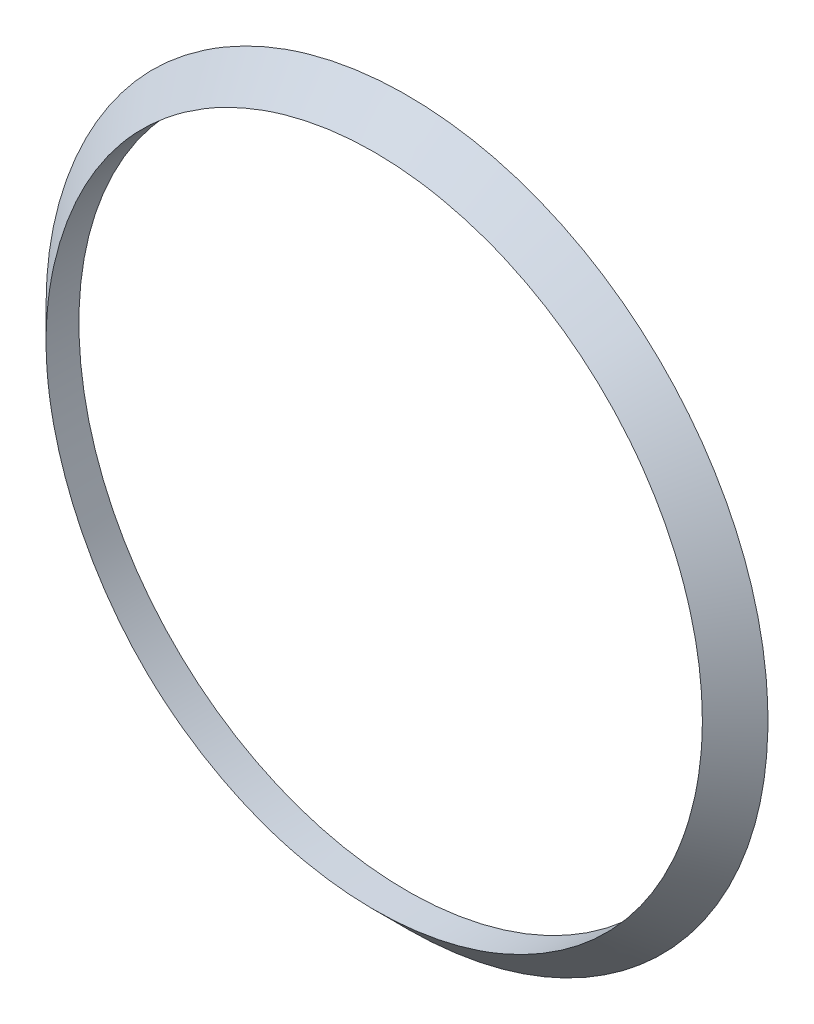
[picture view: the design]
ISO-10303-21;
HEADER;
FILE_DESCRIPTION(('STEP AP214'),'2;1');
FILE_NAME('part.step','',(''),(''),'','','');
FILE_SCHEMA(('AUTOMOTIVE_DESIGN { 1 0 10303 214 1 1 1 1 }'));
ENDSEC;
DATA;
#1=APPLICATION_CONTEXT('core data for automotive mechanical design processes');
#2=APPLICATION_PROTOCOL_DEFINITION('international standard','automotive_design',2000,#1);
#3=PRODUCT_CONTEXT('',#1,'mechanical');
#4=PRODUCT('Part','Part','',(#3));
#5=PRODUCT_RELATED_PRODUCT_CATEGORY('part','',(#4));
#6=PRODUCT_DEFINITION_FORMATION('','',#4);
#7=PRODUCT_DEFINITION_CONTEXT('part definition',#1,'design');
#8=PRODUCT_DEFINITION('design','',#6,#7);
#9=PRODUCT_DEFINITION_SHAPE('','',#8);
#10=(LENGTH_UNIT() NAMED_UNIT(*) SI_UNIT(.MILLI.,.METRE.));
#11=(NAMED_UNIT(*) PLANE_ANGLE_UNIT() SI_UNIT($,.RADIAN.));
#12=(NAMED_UNIT(*) SI_UNIT($,.STERADIAN.) SOLID_ANGLE_UNIT());
#13=UNCERTAINTY_MEASURE_WITH_UNIT(LENGTH_MEASURE(1.E-05),#10,'distance_accuracy_value','');
#14=(GEOMETRIC_REPRESENTATION_CONTEXT(3) GLOBAL_UNCERTAINTY_ASSIGNED_CONTEXT((#13)) GLOBAL_UNIT_ASSIGNED_CONTEXT((#10,
#11,#12)) REPRESENTATION_CONTEXT('',''));
#15=CARTESIAN_POINT('',(0.,0.,0.));
#16=DIRECTION('',(0.,0.,1.));
#17=DIRECTION('',(1.,0.,0.));
#18=AXIS2_PLACEMENT_3D('',#15,#16,#17);
#19=CARTESIAN_POINT('',(71.1493499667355,-109.994408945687,3.));
#20=DIRECTION('',(0.,0.,1.));
#21=DIRECTION('',(1.,0.,0.));
#22=AXIS2_PLACEMENT_3D('',#19,#20,#21);
#23=PLANE('',#22);
#24=CARTESIAN_POINT('',(-22.0000000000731,-312.999999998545,3.));
#25=CARTESIAN_POINT('',(-22.0000009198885,-312.489960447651,3.));
#26=CARTESIAN_POINT('',(-21.9807232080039,-311.979916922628,3.));
#27=CARTESIAN_POINT('',(-21.9049852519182,-310.962587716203,3.));
#28=CARTESIAN_POINT('',(-21.8485211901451,-310.455302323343,3.));
#29=CARTESIAN_POINT('',(-21.6996797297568,-309.445072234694,3.));
#30=CARTESIAN_POINT('',(-21.6072352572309,-308.942137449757,3.));
#31=CARTESIAN_POINT('',(-21.3878172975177,-307.943854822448,3.));
#32=CARTESIAN_POINT('',(-21.2608407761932,-307.4485076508,3.));
#33=CARTESIAN_POINT('',(-20.9361498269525,-306.339509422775,3.));
#34=CARTESIAN_POINT('',(-20.7286230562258,-305.728709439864,3.));
#35=CARTESIAN_POINT('',(-20.2629918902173,-304.526681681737,3.));
#36=CARTESIAN_POINT('',(-20.0048821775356,-303.93545597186,3.));
#37=CARTESIAN_POINT('',(-19.4401801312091,-302.776930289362,3.));
#38=CARTESIAN_POINT('',(-19.1336074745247,-302.209620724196,3.));
#39=CARTESIAN_POINT('',(-18.4735307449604,-301.102885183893,3.));
#40=CARTESIAN_POINT('',(-18.1200267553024,-300.563459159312,3.));
#41=CARTESIAN_POINT('',(-17.4932872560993,-299.691933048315,3.));
#42=CARTESIAN_POINT('',(-17.2326296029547,-299.350715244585,3.));
#43=CARTESIAN_POINT('',(-16.6915818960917,-298.684241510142,3.));
#44=CARTESIAN_POINT('',(-16.4111929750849,-298.358984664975,3.));
#45=CARTESIAN_POINT('',(-15.9762507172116,-297.884381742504,3.));
#46=CARTESIAN_POINT('',(-15.8288809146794,-297.728398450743,3.));
#47=CARTESIAN_POINT('',(-15.5293905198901,-297.421062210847,3.));
#48=CARTESIAN_POINT('',(-15.3772699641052,-297.269709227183,3.));
#49=CARTESIAN_POINT('',(-14.9140155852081,-296.82281921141,3.));
#50=CARTESIAN_POINT('',(-14.5959517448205,-296.53441039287,3.));
#51=CARTESIAN_POINT('',(-13.9429216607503,-295.977345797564,3.));
#52=CARTESIAN_POINT('',(-13.6079524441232,-295.708693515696,3.));
#53=CARTESIAN_POINT('',(-12.9227641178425,-295.191581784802,3.));
#54=CARTESIAN_POINT('',(-12.5725435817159,-294.943124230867,3.));
#55=CARTESIAN_POINT('',(-11.712615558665,-294.36928457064,3.));
#56=CARTESIAN_POINT('',(-11.1961785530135,-294.05391836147,3.));
#57=CARTESIAN_POINT('',(-10.1394984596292,-293.46626115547,3.));
#58=CARTESIAN_POINT('',(-9.59925992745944,-293.193961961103,3.));
#59=CARTESIAN_POINT('',(-8.49818980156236,-292.694884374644,3.));
#60=CARTESIAN_POINT('',(-7.93735994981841,-292.468102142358,3.));
#61=CARTESIAN_POINT('',(-6.7985530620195,-292.062352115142,3.));
#62=CARTESIAN_POINT('',(-6.22057559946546,-291.8833855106,3.));
#63=CARTESIAN_POINT('',(-5.33769615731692,-291.65013219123,3.));
#64=CARTESIAN_POINT('',(-5.03747881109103,-291.577673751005,3.));
#65=CARTESIAN_POINT('',(-4.43420535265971,-291.445628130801,3.));
#66=CARTESIAN_POINT('',(-4.13114922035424,-291.386041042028,3.));
#67=CARTESIAN_POINT('',(-3.52279657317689,-291.279639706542,3.));
#68=CARTESIAN_POINT('',(-3.21749995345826,-291.232826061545,3.));
#69=CARTESIAN_POINT('',(-2.60522718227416,-291.151894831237,3.));
#70=CARTESIAN_POINT('',(-2.29825101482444,-291.11777736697,3.));
#71=CARTESIAN_POINT('',(-1.68304846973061,-291.06226974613,3.));
#72=CARTESIAN_POINT('',(-1.37482173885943,-291.04088348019,3.));
#73=CARTESIAN_POINT('',(-0.757776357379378,-291.010964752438,3.));
#74=CARTESIAN_POINT('',(-0.448957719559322,-291.002432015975,3.));
#75=CARTESIAN_POINT('',(0.477651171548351,-290.996496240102,3.));
#76=CARTESIAN_POINT('',(1.0957243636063,-291.01874375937,3.));
#77=CARTESIAN_POINT('',(2.02118491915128,-291.090536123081,3.));
#78=CARTESIAN_POINT('',(2.33022264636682,-291.121004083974,3.));
#79=CARTESIAN_POINT('',(2.94678812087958,-291.194794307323,3.));
#80=CARTESIAN_POINT('',(3.25431587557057,-291.238116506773,3.));
#81=CARTESIAN_POINT('',(3.86726708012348,-291.337654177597,3.));
#82=CARTESIAN_POINT('',(4.17269060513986,-291.393869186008,3.));
#83=CARTESIAN_POINT('',(4.78083076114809,-291.519323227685,3.));
#84=CARTESIAN_POINT('',(5.08354741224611,-291.588562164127,3.));
#85=CARTESIAN_POINT('',(5.98658512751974,-291.815711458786,3.));
#86=CARTESIAN_POINT('',(6.58213284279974,-291.993109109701,3.));
#87=CARTESIAN_POINT('',(7.7557360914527,-292.398340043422,3.));
#88=CARTESIAN_POINT('',(8.33379073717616,-292.626175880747,3.));
#89=CARTESIAN_POINT('',(9.46362093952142,-293.127659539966,3.));
#90=CARTESIAN_POINT('',(10.0155822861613,-293.400888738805,3.));
#91=CARTESIAN_POINT('',(11.0946944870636,-293.992548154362,3.));
#92=CARTESIAN_POINT('',(11.6218463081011,-294.310976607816,3.));
#93=CARTESIAN_POINT('',(12.6477993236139,-294.990988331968,3.));
#94=CARTESIAN_POINT('',(13.1465907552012,-295.352586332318,3.));
#95=CARTESIAN_POINT('',(14.112250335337,-296.116173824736,3.));
#96=CARTESIAN_POINT('',(14.5791173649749,-296.518164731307,3.));
#97=CARTESIAN_POINT('',(15.4812202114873,-297.362744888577,3.));
#98=CARTESIAN_POINT('',(15.9161901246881,-297.805618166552,3.));
#99=CARTESIAN_POINT('',(16.7474732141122,-298.726251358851,3.));
#100=CARTESIAN_POINT('',(17.1437874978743,-299.204010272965,3.));
#101=CARTESIAN_POINT('',(17.8946717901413,-300.19108890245,3.));
#102=CARTESIAN_POINT('',(18.2492527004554,-300.700400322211,3.));
#103=CARTESIAN_POINT('',(18.9141827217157,-301.747153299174,3.));
#104=CARTESIAN_POINT('',(19.2245296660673,-302.284596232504,3.));
#105=CARTESIAN_POINT('',(19.7994747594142,-303.384937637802,3.));
#106=CARTESIAN_POINT('',(20.0639703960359,-303.947889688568,3.));
#107=CARTESIAN_POINT('',(20.5442509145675,-305.094148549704,3.));
#108=CARTESIAN_POINT('',(20.7600394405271,-305.677453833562,3.));
#109=CARTESIAN_POINT('',(21.140616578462,-306.860696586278,3.));
#110=CARTESIAN_POINT('',(21.3053957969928,-307.460637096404,3.));
#111=CARTESIAN_POINT('',(21.5133539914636,-308.369347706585,3.));
#112=CARTESIAN_POINT('',(21.5761443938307,-308.673761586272,3.));
#113=CARTESIAN_POINT('',(21.6887384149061,-309.285004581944,3.));
#114=CARTESIAN_POINT('',(21.7385418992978,-309.591833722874,3.));
#115=CARTESIAN_POINT('',(21.8247139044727,-310.203355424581,3.));
#116=CARTESIAN_POINT('',(21.8612463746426,-310.508024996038,3.));
#117=CARTESIAN_POINT('',(21.9217458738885,-311.118608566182,3.));
#118=CARTESIAN_POINT('',(21.9457129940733,-311.42452255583,3.));
#119=CARTESIAN_POINT('',(21.9810026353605,-312.037076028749,3.));
#120=CARTESIAN_POINT('',(21.9923253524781,-312.343715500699,3.));
#121=CARTESIAN_POINT('',(22.0020904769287,-312.957198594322,3.));
#122=CARTESIAN_POINT('',(22.0005329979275,-313.264042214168,3.));
#123=CARTESIAN_POINT('',(21.9846004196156,-313.877367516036,3.));
#124=CARTESIAN_POINT('',(21.9702264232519,-314.183849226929,3.));
#125=CARTESIAN_POINT('',(21.9288647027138,-314.795964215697,3.));
#126=CARTESIAN_POINT('',(21.9018767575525,-315.101597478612,3.));
#127=CARTESIAN_POINT('',(21.8353477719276,-315.711496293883,3.));
#128=CARTESIAN_POINT('',(21.7958066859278,-316.015761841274,3.));
#129=CARTESIAN_POINT('',(21.7041659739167,-316.622394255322,3.));
#130=CARTESIAN_POINT('',(21.6520664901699,-316.92476114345,3.));
#131=CARTESIAN_POINT('',(21.5341150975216,-317.532469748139,3.));
#132=CARTESIAN_POINT('',(21.4680319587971,-317.837766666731,3.));
#133=CARTESIAN_POINT('',(21.322705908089,-318.445213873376,3.));
#134=CARTESIAN_POINT('',(21.2434629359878,-318.747364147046,3.));
#135=CARTESIAN_POINT('',(21.0719562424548,-319.347945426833,3.));
#136=CARTESIAN_POINT('',(20.9796925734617,-319.646376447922,3.));
#137=CARTESIAN_POINT('',(20.7823445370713,-320.238968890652,3.));
#138=CARTESIAN_POINT('',(20.6772600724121,-320.533130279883,3.));
#139=CARTESIAN_POINT('',(20.4545556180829,-321.11664916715,3.));
#140=CARTESIAN_POINT('',(20.3369365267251,-321.406007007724,3.));
#141=CARTESIAN_POINT('',(20.0894975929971,-321.979433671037,3.));
#142=CARTESIAN_POINT('',(19.9596777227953,-322.263502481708,3.));
#143=CARTESIAN_POINT('',(19.5522698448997,-323.107028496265,3.));
#144=CARTESIAN_POINT('',(19.2566855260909,-323.657931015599,3.));
#145=CARTESIAN_POINT('',(18.6255201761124,-324.72298484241,3.));
#146=CARTESIAN_POINT('',(18.2907455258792,-325.237616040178,3.));
#147=CARTESIAN_POINT('',(17.5794132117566,-326.237148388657,3.));
#148=CARTESIAN_POINT('',(17.2028567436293,-326.722050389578,3.));
#149=CARTESIAN_POINT('',(16.4107235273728,-327.658976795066,3.));
#150=CARTESIAN_POINT('',(15.9951404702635,-328.110995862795,3.));
#151=CARTESIAN_POINT('',(15.1279722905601,-328.979078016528,3.));
#152=CARTESIAN_POINT('',(14.6763867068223,-329.395140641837,3.));
#153=CARTESIAN_POINT('',(13.7339063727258,-330.193674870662,3.));
#154=CARTESIAN_POINT('',(13.2425644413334,-330.575619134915,3.));
#155=CARTESIAN_POINT('',(12.2293399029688,-331.296574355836,3.));
#156=CARTESIAN_POINT('',(11.7074565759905,-331.635584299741,3.));
#157=CARTESIAN_POINT('',(10.6369590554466,-332.268215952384,3.));
#158=CARTESIAN_POINT('',(10.0883519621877,-332.56184963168,3.));
#159=CARTESIAN_POINT('',(9.24846143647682,-332.966652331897,3.));
#160=CARTESIAN_POINT('',(8.96564021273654,-333.095655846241,3.));
#161=CARTESIAN_POINT('',(8.39476567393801,-333.3415722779,3.));
#162=CARTESIAN_POINT('',(8.10671236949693,-333.458485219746,3.));
#163=CARTESIAN_POINT('',(7.5269162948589,-333.67948654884,3.));
#164=CARTESIAN_POINT('',(7.23519048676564,-333.783619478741,3.));
#165=CARTESIAN_POINT('',(6.64754138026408,-333.979278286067,3.));
#166=CARTESIAN_POINT('',(6.35161811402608,-334.070804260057,3.));
#167=CARTESIAN_POINT('',(5.7561055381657,-334.241055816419,3.));
#168=CARTESIAN_POINT('',(5.45651615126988,-334.31978112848,3.));
#169=CARTESIAN_POINT('',(4.85423419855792,-334.464294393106,3.));
#170=CARTESIAN_POINT('',(4.55154163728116,-334.530082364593,3.));
#171=CARTESIAN_POINT('',(3.94357398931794,-334.648727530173,3.));
#172=CARTESIAN_POINT('',(3.63829840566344,-334.701582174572,3.));
#173=CARTESIAN_POINT('',(3.02580244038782,-334.794485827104,3.));
#174=CARTESIAN_POINT('',(2.7185820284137,-334.834534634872,3.));
#175=CARTESIAN_POINT('',(2.10274390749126,-334.901831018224,3.));
#176=CARTESIAN_POINT('',(1.79412620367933,-334.929078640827,3.));
#177=CARTESIAN_POINT('',(1.17602891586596,-334.970708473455,3.));
#178=CARTESIAN_POINT('',(0.866549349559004,-334.985090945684,3.));
#179=CARTESIAN_POINT('',(0.248739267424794,-335.000740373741,3.));
#180=CARTESIAN_POINT('',(-0.0595896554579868,-335.002069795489,3.));
#181=CARTESIAN_POINT('',(-0.676030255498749,-334.991723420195,3.));
#182=CARTESIAN_POINT('',(-0.984141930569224,-334.980047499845,3.));
#183=CARTESIAN_POINT('',(-1.59962264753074,-334.943934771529,3.));
#184=CARTESIAN_POINT('',(-1.90699166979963,-334.919497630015,3.));
#185=CARTESIAN_POINT('',(-2.52045787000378,-334.857946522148,3.));
#186=CARTESIAN_POINT('',(-2.8265550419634,-334.820832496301,3.));
#187=CARTESIAN_POINT('',(-3.43694185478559,-334.733945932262,3.));
#188=CARTESIAN_POINT('',(-3.74123157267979,-334.684173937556,3.));
#189=CARTESIAN_POINT('',(-4.34742414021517,-334.571871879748,3.));
#190=CARTESIAN_POINT('',(-4.64932701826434,-334.509341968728,3.));
#191=CARTESIAN_POINT('',(-5.55054067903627,-334.302504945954,3.));
#192=CARTESIAN_POINT('',(-6.14555956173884,-334.138921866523,3.));
#193=CARTESIAN_POINT('',(-7.32085880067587,-333.760877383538,3.));
#194=CARTESIAN_POINT('',(-7.90109516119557,-333.546280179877,3.));
#195=CARTESIAN_POINT('',(-9.0413859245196,-333.06850455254,3.));
#196=CARTESIAN_POINT('',(-9.60143766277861,-332.805319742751,3.));
#197=CARTESIAN_POINT('',(-10.423361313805,-332.376319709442,3.));
#198=CARTESIAN_POINT('',(-10.6943081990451,-332.227617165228,3.));
#199=CARTESIAN_POINT('',(-11.2298232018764,-331.919082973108,3.));
#200=CARTESIAN_POINT('',(-11.4943911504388,-331.759251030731,3.));
#201=CARTESIAN_POINT('',(-12.0167119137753,-331.428823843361,3.));
#202=CARTESIAN_POINT('',(-12.2744647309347,-331.258228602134,3.));
#203=CARTESIAN_POINT('',(-12.7826702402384,-330.906532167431,3.));
#204=CARTESIAN_POINT('',(-13.0331234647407,-330.725431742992,3.));
#205=CARTESIAN_POINT('',(-13.6099766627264,-330.289353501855,3.));
#206=CARTESIAN_POINT('',(-13.9332336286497,-330.030199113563,3.));
#207=CARTESIAN_POINT('',(-14.5640670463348,-329.493462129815,3.));
#208=CARTESIAN_POINT('',(-14.8716444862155,-329.215880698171,3.));
#209=CARTESIAN_POINT('',(-15.3201712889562,-328.786196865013,3.));
#210=CARTESIAN_POINT('',(-15.4675420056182,-328.640748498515,3.));
#211=CARTESIAN_POINT('',(-15.757871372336,-328.345514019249,3.));
#212=CARTESIAN_POINT('',(-15.9008300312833,-328.195727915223,3.));
#213=CARTESIAN_POINT('',(-16.3230114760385,-327.740160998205,3.));
#214=CARTESIAN_POINT('',(-16.5955605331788,-327.428151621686,3.));
#215=CARTESIAN_POINT('',(-17.1223900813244,-326.789035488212,3.));
#216=CARTESIAN_POINT('',(-17.3766678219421,-326.461926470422,3.));
#217=CARTESIAN_POINT('',(-17.8665331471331,-325.794014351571,3.));
#218=CARTESIAN_POINT('',(-18.1021201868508,-325.453210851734,3.));
#219=CARTESIAN_POINT('',(-18.6577794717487,-324.600181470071,3.));
#220=CARTESIAN_POINT('',(-18.9671346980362,-324.080925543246,3.));
#221=CARTESIAN_POINT('',(-19.5439362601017,-323.019746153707,3.));
#222=CARTESIAN_POINT('',(-19.8113845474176,-322.477823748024,3.));
#223=CARTESIAN_POINT('',(-20.3029383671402,-321.374653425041,3.));
#224=CARTESIAN_POINT('',(-20.5270467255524,-320.813406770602,3.));
#225=CARTESIAN_POINT('',(-20.9301546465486,-319.675164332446,3.));
#226=CARTESIAN_POINT('',(-21.109160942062,-319.098170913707,3.));
#227=CARTESIAN_POINT('',(-21.5043360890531,-317.615671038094,3.));
#228=CARTESIAN_POINT('',(-21.6882836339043,-316.701190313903,3.));
#229=CARTESIAN_POINT('',(-21.8741391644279,-315.318629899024,3.));
#230=CARTESIAN_POINT('',(-21.921079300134,-314.856145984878,3.));
#231=CARTESIAN_POINT('',(-21.984004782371,-313.929108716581,3.));
#232=CARTESIAN_POINT('',(-21.9999991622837,-313.464556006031,3.));
#233=CARTESIAN_POINT('',(-22.0000000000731,-312.999999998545,3.));
#234=B_SPLINE_CURVE_WITH_KNOTS('',3,(#24,#25,#26,#27,#28,#29,#30,#31,#32,#33,#34,#35,#36,#37,
#38,#39,#40,#41,#42,#43,#44,#45,#46,#47,#48,#49,#50,#51,#52,#53,#54,#55,#56,#57,#58,#59,#60,#61,
#62,#63,#64,#65,#66,#67,#68,#69,#70,#71,#72,#73,#74,#75,#76,#77,#78,#79,#80,#81,#82,#83,#84,#85,
#86,#87,#88,#89,#90,#91,#92,#93,#94,#95,#96,#97,#98,#99,#100,#101,#102,#103,#104,#105,#106,#107,
#108,#109,#110,#111,#112,#113,#114,#115,#116,#117,#118,#119,#120,#121,#122,#123,#124,#125,#126,
#127,#128,#129,#130,#131,#132,#133,#134,#135,#136,#137,#138,#139,#140,#141,#142,#143,#144,#145,
#146,#147,#148,#149,#150,#151,#152,#153,#154,#155,#156,#157,#158,#159,#160,#161,#162,#163,#164,
#165,#166,#167,#168,#169,#170,#171,#172,#173,#174,#175,#176,#177,#178,#179,#180,#181,#182,#183,
#184,#185,#186,#187,#188,#189,#190,#191,#192,#193,#194,#195,#196,#197,#198,#199,#200,#201,#202,
#203,#204,#205,#206,#207,#208,#209,#210,#211,#212,#213,#214,#215,#216,#217,#218,#219,#220,#221,
#222,#223,#224,#225,#226,#227,#228,#229,#230,#231,#232,#233),.UNSPECIFIED.,.T.,.F.,(4,2,2,2,2,2,
2,2,2,2,2,2,2,2,2,2,2,2,2,2,2,2,2,2,2,2,2,2,2,2,2,2,2,2,2,2,2,2,2,2,2,2,2,2,2,2,2,2,2,2,2,2,2,2,
2,2,2,2,2,2,2,2,2,2,2,2,2,2,2,2,2,2,2,2,2,2,2,2,2,2,2,2,2,2,2,2,2,2,2,2,2,2,2,2,2,2,2,2,2,2,2,2,
2,2,4),(0.,1.52978921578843,3.05973550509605,4.59254765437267,6.12549452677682,8.05837481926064,
9.99145840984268,11.9237591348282,13.8560564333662,15.1435614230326,16.4309925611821,
17.0746740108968,17.7183505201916,19.0055381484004,20.2929529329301,21.5804883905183,
23.3937665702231,25.2066991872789,27.0194787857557,28.8323035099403,29.7585825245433,
30.6848681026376,31.6111973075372,32.5375353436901,33.4641563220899,34.3907575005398,
36.2435695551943,37.1749800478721,38.1063859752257,39.0377584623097,39.9691240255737,
41.83082869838,43.6926276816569,45.5381237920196,47.3835479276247,49.2296035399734,
51.0757238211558,52.935804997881,54.795832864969,56.655373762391,58.5150057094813,
60.3787431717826,62.2423411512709,64.106282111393,65.0385164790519,65.9707604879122,
66.8910609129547,67.8113546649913,68.731634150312,69.6519055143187,70.5720976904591,
71.4923059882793,72.4125176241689,73.3327188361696,74.2695275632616,75.2063405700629,
76.1431498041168,77.0799661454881,78.0167153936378,78.9534667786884,80.8265670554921,
82.6662969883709,84.5059742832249,86.3459494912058,88.1859482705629,90.0507062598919,
91.9155082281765,93.7798174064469,94.7121495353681,95.6444797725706,96.5734622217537,
97.5024375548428,98.4314325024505,99.3604260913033,100.289602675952,101.218793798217,
102.147981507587,103.077150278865,104.001870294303,104.92659907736,105.851352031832,
106.776109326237,107.700826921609,108.625533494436,110.474333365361,112.32811098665,
114.182132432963,115.10912895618,116.036150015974,116.963170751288,117.890123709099,
119.132363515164,120.374524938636,120.995620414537,121.616714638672,122.858816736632,
124.101105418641,125.343430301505,127.154679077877,128.965843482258,130.776889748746,
132.587665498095,135.377312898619,136.771087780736,138.16445574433),.UNSPECIFIED.);
#235=CARTESIAN_POINT('',(-22.0000000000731,-312.999999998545,3.));
#236=VERTEX_POINT('',#235);
#237=EDGE_CURVE('E59',#236,#236,#234,.T.);
#238=ORIENTED_EDGE('',*,*,#237,.T.);
#239=EDGE_LOOP('',(#238));
#240=FACE_BOUND('',#239,.T.);
#241=CARTESIAN_POINT('',(0.,-313.,3.));
#242=DIRECTION('',(0.,0.,-1.));
#243=DIRECTION('',(1.,0.,0.));
#244=AXIS2_PLACEMENT_3D('',#241,#242,#243);
#245=CIRCLE('',#244,20.);
#246=CARTESIAN_POINT('',(20.,-313.,3.));
#247=VERTEX_POINT('',#246);
#248=EDGE_CURVE('E69',#247,#247,#245,.T.);
#249=ORIENTED_EDGE('',*,*,#248,.F.);
#250=EDGE_LOOP('',(#249));
#251=FACE_BOUND('',#250,.T.);
#252=ADVANCED_FACE('F52',(#240,#251),#23,.F.);
#253=CARTESIAN_POINT('',(0.,-313.,3.));
#254=DIRECTION('',(0.,0.,-1.));
#255=DIRECTION('',(1.,0.,0.));
#256=AXIS2_PLACEMENT_3D('',#253,#254,#255);
#257=CYLINDRICAL_SURFACE('',#256,20.);
#258=CARTESIAN_POINT('',(-19.999999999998,-312.999999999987,5.));
#259=CARTESIAN_POINT('',(-19.999999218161,-313.506189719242,5.000000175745));
#260=CARTESIAN_POINT('',(-19.9807724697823,-314.01239679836,4.99834207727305));
#261=CARTESIAN_POINT('',(-19.9039746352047,-315.021898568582,4.9932094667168));
#262=CARTESIAN_POINT('',(-19.8464015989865,-315.525193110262,4.98973486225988));
#263=CARTESIAN_POINT('',(-19.693226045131,-316.526075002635,4.98229215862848));
#264=CARTESIAN_POINT('',(-19.5976150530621,-317.023661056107,4.97832394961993));
#265=CARTESIAN_POINT('',(-19.3689140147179,-318.010142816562,4.97096625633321));
#266=CARTESIAN_POINT('',(-19.2358243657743,-318.499038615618,4.96757676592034));
#267=CARTESIAN_POINT('',(-18.9329606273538,-319.46523537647,4.96214507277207));
#268=CARTESIAN_POINT('',(-18.7631936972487,-319.942538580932,4.9601026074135));
#269=CARTESIAN_POINT('',(-18.3879392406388,-320.882889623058,4.95779325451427));
#270=CARTESIAN_POINT('',(-18.182452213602,-321.345937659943,4.95752634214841));
#271=CARTESIAN_POINT('',(-17.7369120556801,-322.255177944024,4.95883506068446));
#272=CARTESIAN_POINT('',(-17.4968532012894,-322.701367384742,4.9604109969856));
#273=CARTESIAN_POINT('',(-16.9835419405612,-323.574291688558,4.96509822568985));
#274=CARTESIAN_POINT('',(-16.7102873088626,-324.001025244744,4.96820962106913));
#275=CARTESIAN_POINT('',(-16.2075100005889,-324.724202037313,4.97434877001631));
#276=CARTESIAN_POINT('',(-15.9851252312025,-325.025639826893,4.97718737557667));
#277=CARTESIAN_POINT('',(-15.5237579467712,-325.615591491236,4.98289464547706));
#278=CARTESIAN_POINT('',(-15.2847741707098,-325.904104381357,4.98576331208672));
#279=CARTESIAN_POINT('',(-14.7909822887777,-326.467260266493,4.99102702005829));
#280=CARTESIAN_POINT('',(-14.5361739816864,-326.741903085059,4.99342205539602));
#281=CARTESIAN_POINT('',(-14.011468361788,-327.276521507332,4.99701571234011));
#282=CARTESIAN_POINT('',(-13.7415673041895,-327.536493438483,4.99821403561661));
#283=CARTESIAN_POINT('',(-13.1875961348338,-328.040865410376,4.99959285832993));
#284=CARTESIAN_POINT('',(-12.9035261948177,-328.285265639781,4.99977337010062));
#285=CARTESIAN_POINT('',(-12.3221012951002,-328.757732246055,4.99961801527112));
#286=CARTESIAN_POINT('',(-12.0247463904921,-328.985798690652,4.99928215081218));
#287=CARTESIAN_POINT('',(-11.4934977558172,-329.370049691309,4.99877810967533));
#288=CARTESIAN_POINT('',(-11.2622919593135,-329.529966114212,4.99858900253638));
#289=CARTESIAN_POINT('',(-10.793327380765,-329.839925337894,4.99849976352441));
#290=CARTESIAN_POINT('',(-10.5555681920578,-329.989967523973,4.99859964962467));
#291=CARTESIAN_POINT('',(-10.073938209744,-330.27989482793,4.99900762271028));
#292=CARTESIAN_POINT('',(-9.8300675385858,-330.419780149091,4.99931570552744));
#293=CARTESIAN_POINT('',(-9.33666946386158,-330.689138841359,5.00007529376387));
#294=CARTESIAN_POINT('',(-9.08714215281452,-330.818612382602,5.00052679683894));
#295=CARTESIAN_POINT('',(-8.33073645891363,-331.191056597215,5.00196670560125));
#296=CARTESIAN_POINT('',(-7.81590625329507,-331.41812793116,5.00304070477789));
#297=CARTESIAN_POINT('',(-6.76904209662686,-331.828070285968,5.00453663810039));
#298=CARTESIAN_POINT('',(-6.23700817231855,-332.010941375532,5.00495857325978));
#299=CARTESIAN_POINT('',(-5.15919719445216,-332.331287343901,5.00477460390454));
#300=CARTESIAN_POINT('',(-4.61341669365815,-332.468750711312,5.00416843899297));
#301=CARTESIAN_POINT('',(-3.78766153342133,-332.640080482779,5.00285454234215));
#302=CARTESIAN_POINT('',(-3.51119111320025,-332.691384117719,5.00234903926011));
#303=CARTESIAN_POINT('',(-2.956340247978,-332.782291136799,5.00143535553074));
#304=CARTESIAN_POINT('',(-2.67795998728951,-332.821895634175,5.00102716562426));
#305=CARTESIAN_POINT('',(-2.11976714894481,-332.889334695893,5.00040400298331));
#306=CARTESIAN_POINT('',(-1.83995449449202,-332.917168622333,5.00018904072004));
#307=CARTESIAN_POINT('',(-1.27940313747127,-332.961015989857,4.99995115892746));
#308=CARTESIAN_POINT('',(-0.998664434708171,-332.977029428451,4.9999282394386));
#309=CARTESIAN_POINT('',(-0.436761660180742,-332.997206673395,4.99995109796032));
#310=CARTESIAN_POINT('',(-0.155597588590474,-333.001370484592,4.99999687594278));
#311=CARTESIAN_POINT('',(0.406654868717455,-332.997841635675,5.00000473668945));
#312=CARTESIAN_POINT('',(0.687743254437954,-332.990148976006,4.9999668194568));
#313=CARTESIAN_POINT('',(1.24935726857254,-332.962919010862,5.00001723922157));
#314=CARTESIAN_POINT('',(1.52988288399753,-332.943381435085,5.00010557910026));
#315=CARTESIAN_POINT('',(2.08984205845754,-332.892501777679,5.00046907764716));
#316=CARTESIAN_POINT('',(2.3692756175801,-332.861159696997,5.0007442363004));
#317=CARTESIAN_POINT('',(3.2052029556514,-332.749495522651,5.0018339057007));
#318=CARTESIAN_POINT('',(3.75944861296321,-332.651529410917,5.0029126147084));
#319=CARTESIAN_POINT('',(4.85764163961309,-332.409266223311,5.00435123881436));
#320=CARTESIAN_POINT('',(5.4015890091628,-332.264969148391,5.0047111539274));
#321=CARTESIAN_POINT('',(6.47541461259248,-331.931061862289,5.00452307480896));
#322=CARTESIAN_POINT('',(7.00529284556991,-331.741451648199,5.00397508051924));
#323=CARTESIAN_POINT('',(8.04717766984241,-331.318272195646,5.00269166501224));
#324=CARTESIAN_POINT('',(8.5591845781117,-331.084703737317,5.00195624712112));
#325=CARTESIAN_POINT('',(9.56170426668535,-330.575265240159,5.00060138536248));
#326=CARTESIAN_POINT('',(10.0522170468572,-330.29939520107,4.99998194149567));
#327=CARTESIAN_POINT('',(11.0082591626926,-329.707315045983,4.99878530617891));
#328=CARTESIAN_POINT('',(11.4737885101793,-329.391104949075,4.99820811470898));
#329=CARTESIAN_POINT('',(12.376555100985,-328.720592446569,4.99716497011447));
#330=CARTESIAN_POINT('',(12.8137923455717,-328.366290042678,4.99669901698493));
#331=CARTESIAN_POINT('',(13.6568769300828,-327.622102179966,4.99612413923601));
#332=CARTESIAN_POINT('',(14.0627234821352,-327.232215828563,4.99601522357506));
#333=CARTESIAN_POINT('',(14.8401289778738,-326.419639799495,4.99622891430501));
#334=CARTESIAN_POINT('',(15.2116879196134,-325.996950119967,4.99655152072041));
#335=CARTESIAN_POINT('',(15.9178769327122,-325.12177182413,4.99743071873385));
#336=CARTESIAN_POINT('',(16.2525069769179,-324.669283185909,4.99798731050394));
#337=CARTESIAN_POINT('',(16.8824586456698,-323.737725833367,4.99913011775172));
#338=CARTESIAN_POINT('',(17.1777802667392,-323.258657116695,4.99971633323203));
#339=CARTESIAN_POINT('',(17.7270136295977,-322.277344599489,5.00097429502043));
#340=CARTESIAN_POINT('',(17.9809258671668,-321.775101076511,5.00164604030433));
#341=CARTESIAN_POINT('',(18.4455341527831,-320.751030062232,5.00306294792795));
#342=CARTESIAN_POINT('',(18.6562302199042,-320.229202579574,5.00380811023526));
#343=CARTESIAN_POINT('',(19.0329288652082,-319.169576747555,5.00465705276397));
#344=CARTESIAN_POINT('',(19.1989314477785,-318.631778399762,5.00476083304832));
#345=CARTESIAN_POINT('',(19.4134889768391,-317.816178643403,5.00424086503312));
#346=CARTESIAN_POINT('',(19.4792725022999,-317.542797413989,5.00395486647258));
#347=CARTESIAN_POINT('',(19.5992619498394,-316.993486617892,5.00320511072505));
#348=CARTESIAN_POINT('',(19.6534678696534,-316.71755705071,5.00274135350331));
#349=CARTESIAN_POINT('',(19.7501960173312,-316.163669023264,5.00183683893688));
#350=CARTESIAN_POINT('',(19.7927185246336,-315.885710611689,5.00139608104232));
#351=CARTESIAN_POINT('',(19.8660084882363,-315.328248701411,5.00068520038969));
#352=CARTESIAN_POINT('',(19.8967759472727,-315.048745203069,5.00041507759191));
#353=CARTESIAN_POINT('',(19.9464981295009,-314.488698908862,5.0000671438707));
#354=CARTESIAN_POINT('',(19.9654535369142,-314.208156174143,4.99998932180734));
#355=CARTESIAN_POINT('',(19.9915257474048,-313.646515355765,4.99995232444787));
#356=CARTESIAN_POINT('',(19.9986411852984,-313.365417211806,4.99999316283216));
#357=CARTESIAN_POINT('',(20.0021846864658,-312.522055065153,5.00000984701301));
#358=CARTESIAN_POINT('',(19.9808238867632,-311.959566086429,4.99987994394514));
#359=CARTESIAN_POINT('',(19.9133296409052,-311.118917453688,5.00028175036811));
#360=CARTESIAN_POINT('',(19.8849175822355,-310.839184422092,5.00051518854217));
#361=CARTESIAN_POINT('',(19.8163262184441,-310.281139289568,5.00116054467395));
#362=CARTESIAN_POINT('',(19.7761469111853,-310.002827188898,5.00157246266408));
#363=CARTESIAN_POINT('',(19.6840898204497,-309.448148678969,5.00246455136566));
#364=CARTESIAN_POINT('',(19.6322121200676,-309.171782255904,5.00294472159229));
#365=CARTESIAN_POINT('',(19.5168588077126,-308.6214982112,5.0037516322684));
#366=CARTESIAN_POINT('',(19.4533831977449,-308.347580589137,5.0040783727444));
#367=CARTESIAN_POINT('',(19.2457127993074,-307.53022669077,5.0047279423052));
#368=CARTESIAN_POINT('',(19.08425385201,-306.991065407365,5.004720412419));
#369=CARTESIAN_POINT('',(18.7165122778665,-305.928335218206,5.00398938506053));
#370=CARTESIAN_POINT('',(18.5102296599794,-305.404766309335,5.00326588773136));
#371=CARTESIAN_POINT('',(18.054287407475,-304.37684623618,5.00185839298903));
#372=CARTESIAN_POINT('',(17.8046277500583,-303.872495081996,5.00117439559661));
#373=CARTESIAN_POINT('',(17.2637096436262,-302.886618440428,4.9998991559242));
#374=CARTESIAN_POINT('',(16.9724509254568,-302.405093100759,4.99930791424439));
#375=CARTESIAN_POINT('',(16.3504051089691,-301.4682879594,4.99815198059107));
#376=CARTESIAN_POINT('',(16.0196180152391,-301.013008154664,4.99758728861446));
#377=CARTESIAN_POINT('',(15.3208672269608,-300.131932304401,4.9966655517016));
#378=CARTESIAN_POINT('',(14.9529035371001,-299.706136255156,4.99630850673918));
#379=CARTESIAN_POINT('',(14.1824152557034,-298.887054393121,4.99601482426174));
#380=CARTESIAN_POINT('',(13.7798906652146,-298.493768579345,4.99607818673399));
#381=CARTESIAN_POINT('',(12.9431316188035,-297.742493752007,4.9965817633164));
#382=CARTESIAN_POINT('',(12.5088963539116,-297.384505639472,4.99702198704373));
#383=CARTESIAN_POINT('',(11.6118121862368,-296.706382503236,4.9980379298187));
#384=CARTESIAN_POINT('',(11.1489632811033,-296.386247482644,4.99861364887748));
#385=CARTESIAN_POINT('',(10.1979419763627,-295.786106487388,4.99980047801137));
#386=CARTESIAN_POINT('',(9.70976958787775,-295.506100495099,5.00041158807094));
#387=CARTESIAN_POINT('',(8.7115736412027,-294.98820821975,5.00174471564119));
#388=CARTESIAN_POINT('',(8.20155008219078,-294.750321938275,5.00246673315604));
#389=CARTESIAN_POINT('',(7.16326433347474,-294.318356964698,5.00379544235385));
#390=CARTESIAN_POINT('',(6.63500193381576,-294.124278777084,5.0044021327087));
#391=CARTESIAN_POINT('',(5.56402566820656,-293.781315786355,5.00475409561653));
#392=CARTESIAN_POINT('',(5.02131180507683,-293.632430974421,5.00449936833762));
#393=CARTESIAN_POINT('',(3.92519449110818,-293.38090431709,5.00317700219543));
#394=CARTESIAN_POINT('',(3.37179103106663,-293.278262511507,5.00210936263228));
#395=CARTESIAN_POINT('',(2.53682933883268,-293.159545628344,5.00094376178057));
#396=CARTESIAN_POINT('',(2.25766804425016,-293.125845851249,5.00062786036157));
#397=CARTESIAN_POINT('',(1.69815375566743,-293.070241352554,5.00018775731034));
#398=CARTESIAN_POINT('',(1.41780076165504,-293.048336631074,5.00006355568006));
#399=CARTESIAN_POINT('',(0.856433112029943,-293.016367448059,4.99996710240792));
#400=CARTESIAN_POINT('',(0.57541847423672,-293.006302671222,4.99999484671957));
#401=CARTESIAN_POINT('',(0.0132133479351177,-292.998028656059,4.99999615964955));
#402=CARTESIAN_POINT('',(-0.267977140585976,-292.99981941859,4.99996972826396));
#403=CARTESIAN_POINT('',(-0.830032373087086,-293.01525373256,4.99993461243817));
#404=CARTESIAN_POINT('',(-1.11089711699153,-293.028897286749,4.99992592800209));
#405=CARTESIAN_POINT('',(-1.67180163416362,-293.068012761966,5.00009164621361));
#406=CARTESIAN_POINT('',(-1.95184140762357,-293.093484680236,5.00026604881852));
#407=CARTESIAN_POINT('',(-2.51059864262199,-293.15621181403,5.0008136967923));
#408=CARTESIAN_POINT('',(-2.78931610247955,-293.193467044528,5.00118694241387));
#409=CARTESIAN_POINT('',(-3.34493120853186,-293.279693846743,5.00206146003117));
#410=CARTESIAN_POINT('',(-3.62182885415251,-293.328665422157,5.00256273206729));
#411=CARTESIAN_POINT('',(-4.17331835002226,-293.438240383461,5.00347859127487));
#412=CARTESIAN_POINT('',(-4.44791020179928,-293.498843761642,5.00389317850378));
#413=CARTESIAN_POINT('',(-4.99427662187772,-293.6315651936,5.00452138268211));
#414=CARTESIAN_POINT('',(-5.26605119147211,-293.703683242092,5.00473499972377));
#415=CARTESIAN_POINT('',(-6.0764492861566,-293.937139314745,5.00500447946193));
#416=CARTESIAN_POINT('',(-6.61025548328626,-294.115600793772,5.00468919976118));
#417=CARTESIAN_POINT('',(-7.66084441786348,-294.51682358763,5.00332106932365));
#418=CARTESIAN_POINT('',(-8.17762714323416,-294.739584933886,5.00226821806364));
#419=CARTESIAN_POINT('',(-9.19066427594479,-295.227895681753,5.00032273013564));
#420=CARTESIAN_POINT('',(-9.68691904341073,-295.493444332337,4.99943009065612));
#421=CARTESIAN_POINT('',(-10.413081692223,-295.922328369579,4.99868937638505));
#422=CARTESIAN_POINT('',(-10.6521285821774,-296.070404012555,4.99854219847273));
#423=CARTESIAN_POINT('',(-11.1237651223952,-296.376496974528,4.99853231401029));
#424=CARTESIAN_POINT('',(-11.3563551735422,-296.534513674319,4.99866958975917));
#425=CARTESIAN_POINT('',(-11.8910437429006,-296.914492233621,4.99913018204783));
#426=CARTESIAN_POINT('',(-12.1904778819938,-297.140216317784,4.99950024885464));
#427=CARTESIAN_POINT('',(-12.7761813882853,-297.608128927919,4.99979363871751));
#428=CARTESIAN_POINT('',(-13.0624507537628,-297.850317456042,4.99971696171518));
#429=CARTESIAN_POINT('',(-13.620927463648,-298.350398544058,4.9986292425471));
#430=CARTESIAN_POINT('',(-13.893134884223,-298.608291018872,4.99761820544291));
#431=CARTESIAN_POINT('',(-14.4226509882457,-299.13898751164,4.99434280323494));
#432=CARTESIAN_POINT('',(-14.6799580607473,-299.41179313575,4.9920783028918));
#433=CARTESIAN_POINT('',(-15.1788360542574,-299.971437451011,4.98697575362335));
#434=CARTESIAN_POINT('',(-15.4204068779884,-300.258276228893,4.98413770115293));
#435=CARTESIAN_POINT('',(-15.8870337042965,-300.845054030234,4.97842454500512));
#436=CARTESIAN_POINT('',(-16.1120898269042,-301.144992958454,4.9755494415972));
#437=CARTESIAN_POINT('',(-16.6532071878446,-301.910066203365,4.96887084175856));
#438=CARTESIAN_POINT('',(-16.9585455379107,-302.382852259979,4.96532136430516));
#439=CARTESIAN_POINT('',(-17.5282915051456,-303.352447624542,4.96012910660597));
#440=CARTESIAN_POINT('',(-17.7926980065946,-303.84925758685,4.95848637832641));
#441=CARTESIAN_POINT('',(-18.2786096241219,-304.863152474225,4.95749630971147));
#442=CARTESIAN_POINT('',(-18.5001349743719,-305.380227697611,4.95814788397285));
#443=CARTESIAN_POINT('',(-18.8988344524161,-306.431147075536,4.96156874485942));
#444=CARTESIAN_POINT('',(-19.0760140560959,-306.964989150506,4.96433776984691));
#445=CARTESIAN_POINT('',(-19.3578601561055,-307.951379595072,4.97066001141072));
#446=CARTESIAN_POINT('',(-19.4697835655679,-308.401872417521,4.97399230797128));
#447=CARTESIAN_POINT('',(-19.6620362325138,-309.309540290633,4.98093441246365));
#448=CARTESIAN_POINT('',(-19.7423671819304,-309.766714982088,4.98454420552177));
#449=CARTESIAN_POINT('',(-19.8710314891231,-310.685434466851,4.99117412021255));
#450=CARTESIAN_POINT('',(-19.9193725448,-311.146978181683,4.9941943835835));
#451=CARTESIAN_POINT('',(-19.983858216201,-312.072342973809,4.99860729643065));
#452=CARTESIAN_POINT('',(-20.0000007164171,-312.536164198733,4.99999983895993));
#453=CARTESIAN_POINT('',(-19.999999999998,-312.999999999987,5.));
#454=B_SPLINE_CURVE_WITH_KNOTS('',3,(#258,#259,#260,#261,#262,#263,#264,#265,#266,#267,#268,
#269,#270,#271,#272,#273,#274,#275,#276,#277,#278,#279,#280,#281,#282,#283,#284,#285,#286,#287,
#288,#289,#290,#291,#292,#293,#294,#295,#296,#297,#298,#299,#300,#301,#302,#303,#304,#305,#306,
#307,#308,#309,#310,#311,#312,#313,#314,#315,#316,#317,#318,#319,#320,#321,#322,#323,#324,#325,
#326,#327,#328,#329,#330,#331,#332,#333,#334,#335,#336,#337,#338,#339,#340,#341,#342,#343,#344,
#345,#346,#347,#348,#349,#350,#351,#352,#353,#354,#355,#356,#357,#358,#359,#360,#361,#362,#363,
#364,#365,#366,#367,#368,#369,#370,#371,#372,#373,#374,#375,#376,#377,#378,#379,#380,#381,#382,
#383,#384,#385,#386,#387,#388,#389,#390,#391,#392,#393,#394,#395,#396,#397,#398,#399,#400,#401,
#402,#403,#404,#405,#406,#407,#408,#409,#410,#411,#412,#413,#414,#415,#416,#417,#418,#419,#420,
#421,#422,#423,#424,#425,#426,#427,#428,#429,#430,#431,#432,#433,#434,#435,#436,#437,#438,#439,
#440,#441,#442,#443,#444,#445,#446,#447,#448,#449,#450,#451,#452,#453),.UNSPECIFIED.,.T.,.F.,(4,
2,2,2,2,2,2,2,2,2,2,2,2,2,2,2,2,2,2,2,2,2,2,2,2,2,2,2,2,2,2,2,2,2,2,2,2,2,2,2,2,2,2,2,2,2,2,2,2,
2,2,2,2,2,2,2,2,2,2,2,2,2,2,2,2,2,2,2,2,2,2,2,2,2,2,2,2,2,2,2,2,2,2,2,2,2,2,2,2,2,2,2,2,2,2,2,2,
4),(0.,1.51823472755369,3.03654666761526,4.55519706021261,6.07383135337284,7.59216947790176,
9.11048637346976,10.6290549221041,12.1477253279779,13.2709830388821,14.3943261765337,
15.5176836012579,16.6413209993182,17.7649447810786,18.8885639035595,19.7316935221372,
20.5748755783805,21.41804075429,22.2611921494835,23.9470479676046,25.6329011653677,
27.3191814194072,28.1625502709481,29.0058388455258,29.8491731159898,30.6925075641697,
31.5358416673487,32.3791757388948,33.2225290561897,34.0658823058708,35.7522139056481,
37.4385454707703,39.1248771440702,40.8111788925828,42.4974806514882,44.1837816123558,
45.8700824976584,47.5564256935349,49.2427689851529,50.9291135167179,52.6154581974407,
54.3017826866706,55.988106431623,57.6744300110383,58.5177796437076,59.3611294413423,
60.2044590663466,61.0477884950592,61.8910690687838,62.734446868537,64.4207302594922,
65.2640596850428,66.1073892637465,66.9507128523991,67.7940362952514,69.4803073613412,
71.1665780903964,72.8528497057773,74.5391322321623,76.2254145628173,77.9116966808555,
79.5979787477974,81.2843038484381,82.9706290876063,84.6569535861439,86.3432781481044,
88.0296221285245,89.7159657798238,91.4023108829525,92.245671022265,93.0890311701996,
93.9323688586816,94.7757066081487,95.6190445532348,96.4623823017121,97.3057211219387,
98.1490602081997,98.9923987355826,99.8357368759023,101.522082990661,103.20843030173,
104.894748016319,105.738121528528,106.581442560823,107.705777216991,108.830112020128,
109.954440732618,111.078890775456,112.203347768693,113.327796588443,115.014146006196,
116.700541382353,118.38613905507,120.071528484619,121.463047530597,122.854492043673,
124.245601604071,125.636802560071),.UNSPECIFIED.);
#455=CARTESIAN_POINT('',(-20.,-312.999999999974,4.99999999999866));
#456=VERTEX_POINT('',#455);
#457=EDGE_CURVE('E11',#456,#456,#454,.T.);
#458=ORIENTED_EDGE('',*,*,#457,.T.);
#459=EDGE_LOOP('',(#458));
#460=FACE_BOUND('',#459,.T.);
#461=ORIENTED_EDGE('',*,*,#248,.T.);
#462=EDGE_LOOP('',(#461));
#463=FACE_BOUND('',#462,.T.);
#464=ADVANCED_FACE('F73',(#460,#463),#257,.F.);
#465=CARTESIAN_POINT('',(-19.9799999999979,-312.999999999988,5.02));
#466=CARTESIAN_POINT('',(-19.9799999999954,-307.761068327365,5.02));
#467=CARTESIAN_POINT('',(-17.1815207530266,-301.212403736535,5.02));
#468=CARTESIAN_POINT('',(-11.2410769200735,-296.338203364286,5.01999999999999));
#469=CARTESIAN_POINT('',(-7.8309629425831,-294.477191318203,5.01999999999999));
#470=CARTESIAN_POINT('',(-4.07907799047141,-293.300029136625,5.01999999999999));
#471=CARTESIAN_POINT('',(-4.75588531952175E-07,-292.880045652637,5.01999999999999));
#472=CARTESIAN_POINT('',(4.07907989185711,-293.299788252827,5.01999999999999));
#473=CARTESIAN_POINT('',(7.83095628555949,-294.478154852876,5.01999999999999));
#474=CARTESIAN_POINT('',(11.241101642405,-296.334590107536,5.01999999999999));
#475=CARTESIAN_POINT('',(14.21120659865,-298.788793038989,5.02));
#476=CARTESIAN_POINT('',(16.6654112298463,-301.758898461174,5.01999999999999));
#477=CARTESIAN_POINT('',(18.5218401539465,-305.16904365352,5.01999999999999));
#478=CARTESIAN_POINT('',(19.7002303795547,-308.920920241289,5.02));
#479=CARTESIAN_POINT('',(20.1198848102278,-313.000000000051,5.01999999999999));
#480=CARTESIAN_POINT('',(19.7002303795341,-317.079079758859,5.02));
#481=CARTESIAN_POINT('',(18.5218401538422,-320.83095634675,5.02));
#482=CARTESIAN_POINT('',(16.6654112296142,-324.241101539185,5.02));
#483=CARTESIAN_POINT('',(14.2112065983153,-327.211206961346,5.02));
#484=CARTESIAN_POINT('',(11.241101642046,-329.665409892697,5.02));
#485=CARTESIAN_POINT('',(7.83095628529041,-331.521845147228,5.02));
#486=CARTESIAN_POINT('',(4.07907989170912,-332.700211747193,5.02));
#487=CARTESIAN_POINT('',(-4.75612603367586E-07,-333.119954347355,5.02));
#488=CARTESIAN_POINT('',(-4.07907799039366,-332.699970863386,5.02));
#489=CARTESIAN_POINT('',(-7.83096294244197,-331.522808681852,5.02));
#490=CARTESIAN_POINT('',(-11.2410769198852,-329.661796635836,5.02));
#491=CARTESIAN_POINT('',(-17.1815207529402,-324.787596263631,5.02));
#492=CARTESIAN_POINT('',(-19.9800000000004,-318.238931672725,5.02));
#493=CARTESIAN_POINT('',(-19.9799999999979,-312.999999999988,5.02));
#494=CARTESIAN_POINT('',(-19.9866666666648,-312.999999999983,5.01333333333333));
#495=CARTESIAN_POINT('',(-19.9866666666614,-307.759320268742,5.01333333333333));
#496=CARTESIAN_POINT('',(-17.1872536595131,-301.20847060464,5.01333333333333));
#497=CARTESIAN_POINT('',(-11.2448276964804,-296.332643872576,5.01333333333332));
#498=CARTESIAN_POINT('',(-7.8335758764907,-294.471010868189,5.01333333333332));
#499=CARTESIAN_POINT('',(-4.08043904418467,-293.29345590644,5.01333333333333));
#500=CARTESIAN_POINT('',(-4.7574546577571E-07,-292.873332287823,5.01333333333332));
#501=CARTESIAN_POINT('',(4.08044094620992,-293.293214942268,5.01333333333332));
#502=CARTESIAN_POINT('',(7.83356921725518,-294.471974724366,5.01333333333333));
#503=CARTESIAN_POINT('',(11.2448524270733,-296.329029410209,5.01333333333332));
#504=CARTESIAN_POINT('',(14.2159484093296,-298.784051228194,5.01333333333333));
#505=CARTESIAN_POINT('',(16.6709719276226,-301.755147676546,5.01333333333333));
#506=CARTESIAN_POINT('',(18.5280202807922,-305.166430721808,5.01333333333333));
#507=CARTESIAN_POINT('',(19.7068036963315,-308.919559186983,5.01333333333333));
#508=CARTESIAN_POINT('',(20.1265981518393,-313.000000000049,5.01333333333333));
#509=CARTESIAN_POINT('',(19.7068036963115,-317.08044081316,5.01333333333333));
#510=CARTESIAN_POINT('',(18.5280202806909,-320.833569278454,5.01333333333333));
#511=CARTESIAN_POINT('',(16.6709719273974,-324.244852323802,5.01333333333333));
#512=CARTESIAN_POINT('',(14.2159484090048,-327.215948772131,5.01333333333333));
#513=CARTESIAN_POINT('',(11.244852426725,-329.670970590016,5.01333333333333));
#514=CARTESIAN_POINT('',(7.83356921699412,-331.528025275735,5.01333333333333));
#515=CARTESIAN_POINT('',(4.08044094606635,-332.706785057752,5.01333333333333));
#516=CARTESIAN_POINT('',(-4.7576934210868E-07,-333.126667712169,5.01333333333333));
#517=CARTESIAN_POINT('',(-4.08043904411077,-332.706544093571,5.01333333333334));
#518=CARTESIAN_POINT('',(-7.83357587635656,-331.528989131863,5.01333333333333));
#519=CARTESIAN_POINT('',(-11.2448276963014,-329.66735612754,5.01333333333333));
#520=CARTESIAN_POINT('',(-17.1872536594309,-324.791529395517,5.01333333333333));
#521=CARTESIAN_POINT('',(-19.9866666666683,-318.240679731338,5.01333333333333));
#522=CARTESIAN_POINT('',(-19.9866666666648,-312.999999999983,5.01333333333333));
#523=CARTESIAN_POINT('',(-19.9933333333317,-312.999999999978,5.00666666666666));
#524=CARTESIAN_POINT('',(-19.9933333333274,-307.757572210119,5.00666666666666));
#525=CARTESIAN_POINT('',(-17.1929865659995,-301.204537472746,5.00666666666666));
#526=CARTESIAN_POINT('',(-11.2485784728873,-296.327084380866,5.00666666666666));
#527=CARTESIAN_POINT('',(-7.8361888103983,-294.464830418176,5.00666666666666));
#528=CARTESIAN_POINT('',(-4.08180009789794,-293.286882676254,5.00666666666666));
#529=CARTESIAN_POINT('',(-4.75902399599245E-07,-292.866618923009,5.00666666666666));
#530=CARTESIAN_POINT('',(4.08180200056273,-293.286641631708,5.00666666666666));
#531=CARTESIAN_POINT('',(7.83618214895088,-294.465794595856,5.00666666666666));
#532=CARTESIAN_POINT('',(11.2486032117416,-296.323468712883,5.00666666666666));
#533=CARTESIAN_POINT('',(14.2206902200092,-298.779309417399,5.00666666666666));
#534=CARTESIAN_POINT('',(16.6765326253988,-301.751396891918,5.00666666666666));
#535=CARTESIAN_POINT('',(18.5342004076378,-305.163817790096,5.00666666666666));
#536=CARTESIAN_POINT('',(19.7133770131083,-308.918198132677,5.00666666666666));
#537=CARTESIAN_POINT('',(20.1333114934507,-313.000000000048,5.00666666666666));
#538=CARTESIAN_POINT('',(19.7133770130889,-317.081801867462,5.00666666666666));
#539=CARTESIAN_POINT('',(18.5342004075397,-320.836182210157,5.00666666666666));
#540=CARTESIAN_POINT('',(16.6765326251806,-324.24860310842,5.00666666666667));
#541=CARTESIAN_POINT('',(14.2206902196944,-327.220690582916,5.00666666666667));
#542=CARTESIAN_POINT('',(11.2486032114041,-329.676531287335,5.00666666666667));
#543=CARTESIAN_POINT('',(7.83618214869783,-331.534205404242,5.00666666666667));
#544=CARTESIAN_POINT('',(4.08180200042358,-332.713358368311,5.00666666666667));
#545=CARTESIAN_POINT('',(-4.75926080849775E-07,-333.133381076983,5.00666666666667));
#546=CARTESIAN_POINT('',(-4.08180009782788,-332.713117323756,5.00666666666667));
#547=CARTESIAN_POINT('',(-7.83618881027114,-331.535169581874,5.00666666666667));
#548=CARTESIAN_POINT('',(-11.2485784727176,-329.672915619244,5.00666666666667));
#549=CARTESIAN_POINT('',(-17.1929865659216,-324.795462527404,5.00666666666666));
#550=CARTESIAN_POINT('',(-19.9933333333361,-318.242427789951,5.00666666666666));
#551=CARTESIAN_POINT('',(-19.9933333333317,-312.999999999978,5.00666666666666));
#552=CARTESIAN_POINT('',(-19.9999999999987,-312.999999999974,5.));
#553=CARTESIAN_POINT('',(-19.9999999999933,-307.755824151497,5.));
#554=CARTESIAN_POINT('',(-17.1987194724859,-301.200604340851,5.));
#555=CARTESIAN_POINT('',(-11.2523292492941,-296.321524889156,4.99999999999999));
#556=CARTESIAN_POINT('',(-7.83880174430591,-294.458649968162,4.99999999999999));
#557=CARTESIAN_POINT('',(-4.0831611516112,-293.280309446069,4.99999999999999));
#558=CARTESIAN_POINT('',(-4.7605933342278E-07,-292.859905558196,4.99999999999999));
#559=CARTESIAN_POINT('',(4.08316305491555,-293.280068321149,4.99999999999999));
#560=CARTESIAN_POINT('',(7.83879508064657,-294.459614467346,4.99999999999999));
#561=CARTESIAN_POINT('',(11.25235399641,-296.317908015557,4.99999999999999));
#562=CARTESIAN_POINT('',(14.2254320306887,-298.774567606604,4.99999999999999));
#563=CARTESIAN_POINT('',(16.6820933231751,-301.74764610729,4.99999999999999));
#564=CARTESIAN_POINT('',(18.5403805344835,-305.161204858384,4.99999999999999));
#565=CARTESIAN_POINT('',(19.7199503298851,-308.916837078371,4.99999999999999));
#566=CARTESIAN_POINT('',(20.1400248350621,-313.000000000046,4.99999999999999));
#567=CARTESIAN_POINT('',(19.7199503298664,-317.083162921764,5.));
#568=CARTESIAN_POINT('',(18.5403805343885,-320.838795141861,5.));
#569=CARTESIAN_POINT('',(16.6820933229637,-324.252353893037,5.));
#570=CARTESIAN_POINT('',(14.2254320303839,-327.225432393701,5.));
#571=CARTESIAN_POINT('',(11.2523539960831,-329.682091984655,5.));
#572=CARTESIAN_POINT('',(7.83879508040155,-331.540385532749,5.));
#573=CARTESIAN_POINT('',(4.0831630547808,-332.71993167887,5.));
#574=CARTESIAN_POINT('',(-4.7608281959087E-07,-333.140094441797,5.));
#575=CARTESIAN_POINT('',(-4.08316115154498,-332.71969055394,5.));
#576=CARTESIAN_POINT('',(-7.83880174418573,-331.541350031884,5.));
#577=CARTESIAN_POINT('',(-11.2523292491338,-329.678475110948,5.));
#578=CARTESIAN_POINT('',(-17.1987194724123,-324.799395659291,5.));
#579=CARTESIAN_POINT('',(-20.000000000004,-318.244175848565,5.));
#580=CARTESIAN_POINT('',(-19.9999999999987,-312.999999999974,5.));
#581=CARTESIAN_POINT('',(-20.6666666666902,-312.999999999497,4.33333333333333));
#582=CARTESIAN_POINT('',(-20.6666666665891,-307.581018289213,4.33333333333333));
#583=CARTESIAN_POINT('',(-17.77201012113,-300.80729115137,4.33333333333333));
#584=CARTESIAN_POINT('',(-11.6274068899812,-295.765575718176,4.33333333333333));
#585=CARTESIAN_POINT('',(-8.10009513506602,-293.840604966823,4.33333333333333));
#586=CARTESIAN_POINT('',(-4.21926652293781,-292.62298642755,4.33333333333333));
#587=CARTESIAN_POINT('',(-4.91752715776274E-07,-292.188569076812,4.33333333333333));
#588=CARTESIAN_POINT('',(4.21926849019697,-292.622737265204,4.33333333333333));
#589=CARTESIAN_POINT('',(8.10008825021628,-293.841601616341,4.33333333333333));
#590=CARTESIAN_POINT('',(11.6274324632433,-295.761838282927,4.33333333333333));
#591=CARTESIAN_POINT('',(14.6996130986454,-298.300386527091,4.33333333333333));
#592=CARTESIAN_POINT('',(17.2381631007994,-301.372567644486,4.33333333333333));
#593=CARTESIAN_POINT('',(19.1583932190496,-304.899911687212,4.33333333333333));
#594=CARTESIAN_POINT('',(20.3772820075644,-308.780731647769,4.33333333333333));
#595=CARTESIAN_POINT('',(20.8113589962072,-312.999999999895,4.33333333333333));
#596=CARTESIAN_POINT('',(20.377282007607,-317.219268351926,4.33333333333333));
#597=CARTESIAN_POINT('',(19.1583932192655,-321.100088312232,4.33333333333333));
#598=CARTESIAN_POINT('',(17.2381631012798,-324.627432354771,4.33333333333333));
#599=CARTESIAN_POINT('',(14.6996130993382,-327.699613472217,4.33333333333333));
#600=CARTESIAN_POINT('',(11.6274324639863,-330.238161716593,4.33333333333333));
#601=CARTESIAN_POINT('',(8.1000882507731,-332.158398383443,4.33333333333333));
#602=CARTESIAN_POINT('',(4.21926849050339,-333.377262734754,4.33333333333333));
#603=CARTESIAN_POINT('',(-4.91756693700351E-07,-333.81143092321,4.33333333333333));
#604=CARTESIAN_POINT('',(-4.21926652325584,-333.377013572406,4.33333333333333));
#605=CARTESIAN_POINT('',(-8.10009513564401,-332.159395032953,4.33333333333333));
#606=CARTESIAN_POINT('',(-11.6274068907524,-330.234424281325,4.33333333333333));
#607=CARTESIAN_POINT('',(-17.7720101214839,-325.192708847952,4.33333333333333));
#608=CARTESIAN_POINT('',(-20.6666666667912,-318.418981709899,4.33333333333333));
#609=CARTESIAN_POINT('',(-20.6666666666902,-312.999999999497,4.33333333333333));
#610=CARTESIAN_POINT('',(-21.3333333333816,-312.999999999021,3.66666666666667));
#611=CARTESIAN_POINT('',(-21.3333333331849,-307.40621242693,3.66666666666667));
#612=CARTESIAN_POINT('',(-18.345300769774,-300.41397796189,3.66666666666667));
#613=CARTESIAN_POINT('',(-12.0024845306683,-295.209626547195,3.66666666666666));
#614=CARTESIAN_POINT('',(-8.36138852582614,-293.222559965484,3.66666666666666));
#615=CARTESIAN_POINT('',(-4.35537189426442,-291.965663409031,3.66666666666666));
#616=CARTESIAN_POINT('',(-5.07446097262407E-07,-291.517232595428,3.66666666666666));
#617=CARTESIAN_POINT('',(4.35537392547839,-291.965406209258,3.66666666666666));
#618=CARTESIAN_POINT('',(8.36138141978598,-293.223588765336,3.66666666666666));
#619=CARTESIAN_POINT('',(12.0025109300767,-295.205768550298,3.66666666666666));
#620=CARTESIAN_POINT('',(15.1737941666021,-297.826205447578,3.66666666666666));
#621=CARTESIAN_POINT('',(17.7942328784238,-300.997489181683,3.66666666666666));
#622=CARTESIAN_POINT('',(19.7764059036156,-304.638618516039,3.66666666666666));
#623=CARTESIAN_POINT('',(21.0346136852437,-308.644626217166,3.66666666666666));
#624=CARTESIAN_POINT('',(21.4826931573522,-312.999999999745,3.66666666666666));
#625=CARTESIAN_POINT('',(21.0346136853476,-317.355373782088,3.66666666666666));
#626=CARTESIAN_POINT('',(19.7764059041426,-321.361381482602,3.66666666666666));
#627=CARTESIAN_POINT('',(17.7942328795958,-325.002510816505,3.66666666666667));
#628=CARTESIAN_POINT('',(15.1737941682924,-328.173794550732,3.66666666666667));
#629=CARTESIAN_POINT('',(12.0025109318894,-330.79423144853,3.66666666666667));
#630=CARTESIAN_POINT('',(8.36138142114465,-332.776411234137,3.66666666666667));
#631=CARTESIAN_POINT('',(4.35537392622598,-334.034593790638,3.66666666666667));
#632=CARTESIAN_POINT('',(-5.07430566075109E-07,-334.482767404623,3.66666666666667));
#633=CARTESIAN_POINT('',(-4.3553718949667,-334.034336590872,3.66666666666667));
#634=CARTESIAN_POINT('',(-8.3613885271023,-332.777440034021,3.66666666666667));
#635=CARTESIAN_POINT('',(-12.002484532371,-330.790373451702,3.66666666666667));
#636=CARTESIAN_POINT('',(-18.3453007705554,-325.586022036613,3.66666666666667));
#637=CARTESIAN_POINT('',(-21.3333333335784,-318.593787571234,3.66666666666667));
#638=CARTESIAN_POINT('',(-21.3333333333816,-312.999999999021,3.66666666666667));
#639=CARTESIAN_POINT('',(-22.0000000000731,-312.999999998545,3.));
#640=CARTESIAN_POINT('',(-21.9999999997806,-307.231406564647,3.));
#641=CARTESIAN_POINT('',(-18.9185914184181,-300.020664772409,3.));
#642=CARTESIAN_POINT('',(-12.3775621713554,-294.653677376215,3.));
#643=CARTESIAN_POINT('',(-8.62268191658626,-292.604514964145,3.));
#644=CARTESIAN_POINT('',(-4.49147726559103,-291.308340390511,3.));
#645=CARTESIAN_POINT('',(-5.23139479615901E-07,-290.845896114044,3.));
#646=CARTESIAN_POINT('',(4.49147936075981,-291.308075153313,3.));
#647=CARTESIAN_POINT('',(8.62267458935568,-292.60557591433,3.));
#648=CARTESIAN_POINT('',(12.3775893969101,-294.649698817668,3.));
#649=CARTESIAN_POINT('',(15.6479752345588,-297.352024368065,3.));
#650=CARTESIAN_POINT('',(18.3503026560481,-300.622410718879,3.));
#651=CARTESIAN_POINT('',(20.3944185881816,-304.377325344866,3.));
#652=CARTESIAN_POINT('',(21.6919453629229,-308.508520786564,3.));
#653=CARTESIAN_POINT('',(22.1540273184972,-312.999999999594,3.));
#654=CARTESIAN_POINT('',(21.6919453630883,-317.49147921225,3.));
#655=CARTESIAN_POINT('',(20.3944185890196,-321.622674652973,3.));
#656=CARTESIAN_POINT('',(18.3503026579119,-325.377589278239,3.));
#657=CARTESIAN_POINT('',(15.6479752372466,-328.647975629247,3.));
#658=CARTESIAN_POINT('',(12.3775893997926,-331.350301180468,3.));
#659=CARTESIAN_POINT('',(8.6226745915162,-333.394424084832,3.));
#660=CARTESIAN_POINT('',(4.49147936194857,-334.691924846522,3.));
#661=CARTESIAN_POINT('',(-5.23104438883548E-07,-335.154103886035,3.));
#662=CARTESIAN_POINT('',(-4.49147726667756,-334.691659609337,3.));
#663=CARTESIAN_POINT('',(-8.62268191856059,-333.39548503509,3.));
#664=CARTESIAN_POINT('',(-12.3775621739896,-331.34632262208,3.));
#665=CARTESIAN_POINT('',(-18.918591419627,-325.979335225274,3.));
#666=CARTESIAN_POINT('',(-22.0000000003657,-318.768593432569,3.));
#667=CARTESIAN_POINT('',(-22.0000000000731,-312.999999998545,3.));
#668=B_SPLINE_SURFACE_WITH_KNOTS('',3,3,((#465,#466,#467,#468,#469,#470,#471,#472,#473,#474,
#475,#476,#477,#478,#479,#480,#481,#482,#483,#484,#485,#486,#487,#488,#489,#490,#491,#492,#493),
(#494,#495,#496,#497,#498,#499,#500,#501,#502,#503,#504,#505,#506,#507,#508,#509,#510,#511,#512,
#513,#514,#515,#516,#517,#518,#519,#520,#521,#522),(#523,#524,#525,#526,#527,#528,#529,#530,
#531,#532,#533,#534,#535,#536,#537,#538,#539,#540,#541,#542,#543,#544,#545,#546,#547,#548,#549,
#550,#551),(#552,#553,#554,#555,#556,#557,#558,#559,#560,#561,#562,#563,#564,#565,#566,#567,
#568,#569,#570,#571,#572,#573,#574,#575,#576,#577,#578,#579,#580),(#581,#582,#583,#584,#585,
#586,#587,#588,#589,#590,#591,#592,#593,#594,#595,#596,#597,#598,#599,#600,#601,#602,#603,#604,
#605,#606,#607,#608,#609),(#610,#611,#612,#613,#614,#615,#616,#617,#618,#619,#620,#621,#622,
#623,#624,#625,#626,#627,#628,#629,#630,#631,#632,#633,#634,#635,#636,#637,#638),(#639,#640,
#641,#642,#643,#644,#645,#646,#647,#648,#649,#650,#651,#652,#653,#654,#655,#656,#657,#658,#659,
#660,#661,#662,#663,#664,#665,#666,#667)),.UNSPECIFIED.,.F.,.T.,.F.,(4,3,4),(4,1,1,1,1,1,1,1,1,
1,1,1,1,1,1,1,1,1,1,1,1,1,1,1,1,1,4),(-0.01,0.,1.),(0.,0.124999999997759,0.156249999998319,
0.18749999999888,0.21874999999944,0.25,0.2812499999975,0.312499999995,0.3437499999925,
0.37499999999,0.4062499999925,0.437499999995,0.4687499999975,0.5,0.531249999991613,
0.562499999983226,0.593749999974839,0.624999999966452,0.656249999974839,0.687499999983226,
0.718749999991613,0.75,0.781249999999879,0.812499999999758,0.843749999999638,0.874999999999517,
1.),.UNSPECIFIED.);
#669=CARTESIAN_POINT('',(-20.,-312.999999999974,4.99999999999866));
#670=CARTESIAN_POINT('',(-20.0208333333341,-312.999999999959,4.97916666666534));
#671=CARTESIAN_POINT('',(-20.0416666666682,-312.999999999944,4.95833333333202));
#672=CARTESIAN_POINT('',(-20.0833333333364,-312.999999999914,4.91666666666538));
#673=CARTESIAN_POINT('',(-20.1041666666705,-312.999999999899,4.89583333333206));
#674=CARTESIAN_POINT('',(-20.1458333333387,-312.999999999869,4.85416666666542));
#675=CARTESIAN_POINT('',(-20.1666666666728,-312.999999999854,4.8333333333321));
#676=CARTESIAN_POINT('',(-20.2083333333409,-312.999999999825,4.79166666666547));
#677=CARTESIAN_POINT('',(-20.229166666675,-312.99999999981,4.77083333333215));
#678=CARTESIAN_POINT('',(-20.2708333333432,-312.99999999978,4.72916666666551));
#679=CARTESIAN_POINT('',(-20.2916666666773,-312.999999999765,4.70833333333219));
#680=CARTESIAN_POINT('',(-20.3333333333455,-312.999999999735,4.66666666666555));
#681=CARTESIAN_POINT('',(-20.3541666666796,-312.999999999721,4.64583333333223));
#682=CARTESIAN_POINT('',(-20.3958333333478,-312.999999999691,4.60416666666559));
#683=CARTESIAN_POINT('',(-20.4166666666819,-312.999999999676,4.58333333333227));
#684=CARTESIAN_POINT('',(-20.4583333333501,-312.999999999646,4.54166666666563));
#685=CARTESIAN_POINT('',(-20.4791666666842,-312.999999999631,4.52083333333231));
#686=CARTESIAN_POINT('',(-20.5208333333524,-312.999999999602,4.47916666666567));
#687=CARTESIAN_POINT('',(-20.5416666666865,-312.999999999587,4.45833333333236));
#688=CARTESIAN_POINT('',(-20.5833333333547,-312.999999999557,4.41666666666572));
#689=CARTESIAN_POINT('',(-20.6041666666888,-312.999999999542,4.3958333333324));
#690=CARTESIAN_POINT('',(-20.6458333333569,-312.999999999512,4.35416666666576));
#691=CARTESIAN_POINT('',(-20.666666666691,-312.999999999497,4.33333333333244));
#692=CARTESIAN_POINT('',(-20.7083333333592,-312.999999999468,4.2916666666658));
#693=CARTESIAN_POINT('',(-20.7291666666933,-312.999999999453,4.27083333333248));
#694=CARTESIAN_POINT('',(-20.7708333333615,-312.999999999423,4.22916666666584));
#695=CARTESIAN_POINT('',(-20.7916666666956,-312.999999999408,4.20833333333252));
#696=CARTESIAN_POINT('',(-20.8333333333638,-312.999999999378,4.16666666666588));
#697=CARTESIAN_POINT('',(-20.8541666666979,-312.999999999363,4.14583333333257));
#698=CARTESIAN_POINT('',(-20.8958333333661,-312.999999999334,4.10416666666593));
#699=CARTESIAN_POINT('',(-20.9166666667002,-312.999999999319,4.08333333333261));
#700=CARTESIAN_POINT('',(-20.9583333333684,-312.999999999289,4.04166666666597));
#701=CARTESIAN_POINT('',(-20.9791666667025,-312.999999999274,4.02083333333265));
#702=CARTESIAN_POINT('',(-21.0208333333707,-312.999999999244,3.97916666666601));
#703=CARTESIAN_POINT('',(-21.0416666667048,-312.99999999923,3.95833333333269));
#704=CARTESIAN_POINT('',(-21.0833333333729,-312.9999999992,3.91666666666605));
#705=CARTESIAN_POINT('',(-21.104166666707,-312.999999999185,3.89583333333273));
#706=CARTESIAN_POINT('',(-21.1458333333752,-312.999999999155,3.85416666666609));
#707=CARTESIAN_POINT('',(-21.1666666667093,-312.99999999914,3.83333333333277));
#708=CARTESIAN_POINT('',(-21.2083333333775,-312.99999999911,3.79166666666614));
#709=CARTESIAN_POINT('',(-21.2291666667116,-312.999999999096,3.77083333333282));
#710=CARTESIAN_POINT('',(-21.2708333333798,-312.999999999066,3.72916666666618));
#711=CARTESIAN_POINT('',(-21.2916666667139,-312.999999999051,3.70833333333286));
#712=CARTESIAN_POINT('',(-21.3333333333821,-312.999999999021,3.66666666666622));
#713=CARTESIAN_POINT('',(-21.3541666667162,-312.999999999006,3.6458333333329));
#714=CARTESIAN_POINT('',(-21.3958333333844,-312.999999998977,3.60416666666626));
#715=CARTESIAN_POINT('',(-21.4166666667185,-312.999999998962,3.58333333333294));
#716=CARTESIAN_POINT('',(-21.4583333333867,-312.999999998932,3.5416666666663));
#717=CARTESIAN_POINT('',(-21.4791666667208,-312.999999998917,3.52083333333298));
#718=CARTESIAN_POINT('',(-21.5208333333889,-312.999999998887,3.47916666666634));
#719=CARTESIAN_POINT('',(-21.541666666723,-312.999999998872,3.45833333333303));
#720=CARTESIAN_POINT('',(-21.5833333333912,-312.999999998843,3.41666666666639));
#721=CARTESIAN_POINT('',(-21.6041666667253,-312.999999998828,3.39583333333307));
#722=CARTESIAN_POINT('',(-21.6458333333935,-312.999999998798,3.35416666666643));
#723=CARTESIAN_POINT('',(-21.6666666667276,-312.999999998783,3.33333333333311));
#724=CARTESIAN_POINT('',(-21.7083333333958,-312.999999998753,3.29166666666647));
#725=CARTESIAN_POINT('',(-21.7291666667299,-312.999999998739,3.27083333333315));
#726=CARTESIAN_POINT('',(-21.7708333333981,-312.999999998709,3.22916666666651));
#727=CARTESIAN_POINT('',(-21.7916666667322,-312.999999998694,3.20833333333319));
#728=CARTESIAN_POINT('',(-21.8333333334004,-312.999999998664,3.16666666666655));
#729=CARTESIAN_POINT('',(-21.8541666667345,-312.999999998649,3.14583333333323));
#730=CARTESIAN_POINT('',(-21.8958333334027,-312.99999999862,3.1041666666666));
#731=CARTESIAN_POINT('',(-21.9166666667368,-312.999999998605,3.08333333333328));
#732=CARTESIAN_POINT('',(-21.9583333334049,-312.999999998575,3.04166666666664));
#733=CARTESIAN_POINT('',(-21.979166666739,-312.99999999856,3.02083333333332));
#734=CARTESIAN_POINT('',(-22.0000000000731,-312.999999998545,3.));
#735=B_SPLINE_CURVE_WITH_KNOTS('',3,(#669,#670,#671,#672,#673,#674,#675,#676,#677,#678,#679,
#680,#681,#682,#683,#684,#685,#686,#687,#688,#689,#690,#691,#692,#693,#694,#695,#696,#697,#698,
#699,#700,#701,#702,#703,#704,#705,#706,#707,#708,#709,#710,#711,#712,#713,#714,#715,#716,#717,
#718,#719,#720,#721,#722,#723,#724,#725,#726,#727,#728,#729,#730,#731,#732,#733,#734),
.UNSPECIFIED.,.F.,.F.,(4,2,2,2,2,2,2,2,2,2,2,2,2,2,2,2,2,2,2,2,2,2,2,2,2,2,2,2,2,2,2,2,4),(0.,
0.0883883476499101,0.17677669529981,0.26516504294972,0.353553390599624,0.44194173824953,
0.530330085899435,0.618718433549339,0.707106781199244,0.795495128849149,0.883883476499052,
0.972271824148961,1.06066017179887,1.14904851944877,1.23743686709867,1.32582521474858,
1.41421356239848,1.50260191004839,1.59099025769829,1.6793786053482,1.7677669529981,
1.85615530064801,1.94454364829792,2.03293199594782,2.12132034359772,2.20970869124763,
2.29809703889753,2.38648538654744,2.47487373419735,2.56326208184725,2.65165042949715,
2.74003877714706,2.82842712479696),.UNSPECIFIED.);
#736=EDGE_CURVE('BSEAM54',#456,#236,#735,.T.);
#737=ORIENTED_EDGE('',*,*,#457,.F.);
#738=ORIENTED_EDGE('',*,*,#237,.F.);
#739=ORIENTED_EDGE('',*,*,#736,.T.);
#740=ORIENTED_EDGE('',*,*,#736,.F.);
#741=EDGE_LOOP('',(#737,#739,#738,#740));
#742=FACE_BOUND('',#741,.T.);
#743=ADVANCED_FACE('F54',(#742),#668,.F.);
#744=CLOSED_SHELL('',(#252,#464,#743));
#745=MANIFOLD_SOLID_BREP('B2',#744);
#746=ADVANCED_BREP_SHAPE_REPRESENTATION('',(#18,#745),#14);
#747=SHAPE_DEFINITION_REPRESENTATION(#9,#746);
ENDSEC;
END-ISO-10303-21;
